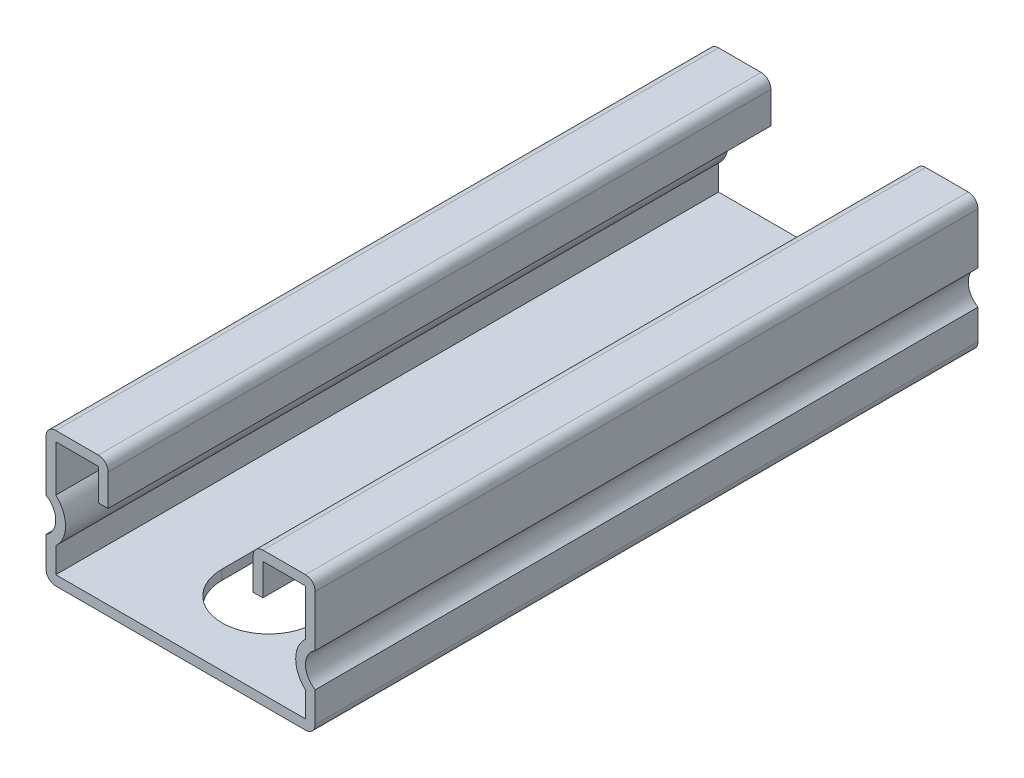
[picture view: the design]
ISO-10303-21;
HEADER;
FILE_DESCRIPTION(('STEP AP214'),'2;1');
FILE_NAME('part.step','',(''),(''),'','','');
FILE_SCHEMA(('AUTOMOTIVE_DESIGN { 1 0 10303 214 1 1 1 1 }'));
ENDSEC;
DATA;
#1=APPLICATION_CONTEXT('core data for automotive mechanical design processes');
#2=APPLICATION_PROTOCOL_DEFINITION('international standard','automotive_design',2000,#1);
#3=PRODUCT_CONTEXT('',#1,'mechanical');
#4=PRODUCT('Part','Part','',(#3));
#5=PRODUCT_RELATED_PRODUCT_CATEGORY('part','',(#4));
#6=PRODUCT_DEFINITION_FORMATION('','',#4);
#7=PRODUCT_DEFINITION_CONTEXT('part definition',#1,'design');
#8=PRODUCT_DEFINITION('design','',#6,#7);
#9=PRODUCT_DEFINITION_SHAPE('','',#8);
#10=(LENGTH_UNIT() NAMED_UNIT(*) SI_UNIT(.MILLI.,.METRE.));
#11=(NAMED_UNIT(*) PLANE_ANGLE_UNIT() SI_UNIT($,.RADIAN.));
#12=(NAMED_UNIT(*) SI_UNIT($,.STERADIAN.) SOLID_ANGLE_UNIT());
#13=UNCERTAINTY_MEASURE_WITH_UNIT(LENGTH_MEASURE(1.E-05),#10,'distance_accuracy_value','');
#14=(GEOMETRIC_REPRESENTATION_CONTEXT(3) GLOBAL_UNCERTAINTY_ASSIGNED_CONTEXT((#13)) GLOBAL_UNIT_ASSIGNED_CONTEXT((#10,
#11,#12)) REPRESENTATION_CONTEXT('',''));
#15=CARTESIAN_POINT('',(0.,0.,0.));
#16=DIRECTION('',(0.,0.,1.));
#17=DIRECTION('',(1.,0.,0.));
#18=AXIS2_PLACEMENT_3D('',#15,#16,#17);
#19=CARTESIAN_POINT('',(-19.1389,10.4394,101.6));
#20=DIRECTION('',(-1.,0.,0.));
#21=DIRECTION('',(0.,0.,1.));
#22=AXIS2_PLACEMENT_3D('',#19,#20,#21);
#23=PLANE('',#22);
#24=DIRECTION('',(0.,1.,0.));
#25=VECTOR('',#24,1.);
#26=CARTESIAN_POINT('',(-19.1389,10.4394,0.));
#27=LINE('',#26,#25);
#28=CARTESIAN_POINT('',(-19.1389,3.35097147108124,0.));
#29=VERTEX_POINT('',#28);
#30=CARTESIAN_POINT('',(-19.1389,10.4394,0.));
#31=VERTEX_POINT('',#30);
#32=EDGE_CURVE('E326',#29,#31,#27,.T.);
#33=ORIENTED_EDGE('',*,*,#32,.T.);
#34=DIRECTION('',(0.,0.,-1.));
#35=VECTOR('',#34,1.);
#36=CARTESIAN_POINT('',(-19.1389,10.4394,101.6));
#37=LINE('',#36,#35);
#38=CARTESIAN_POINT('',(-19.1389,10.4394,101.6));
#39=VERTEX_POINT('',#38);
#40=EDGE_CURVE('E541',#39,#31,#37,.T.);
#41=ORIENTED_EDGE('',*,*,#40,.F.);
#42=DIRECTION('',(0.,1.,0.));
#43=VECTOR('',#42,1.);
#44=CARTESIAN_POINT('',(-19.1389,10.4394,101.6));
#45=LINE('',#44,#43);
#46=CARTESIAN_POINT('',(-19.1389,3.35097147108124,101.6));
#47=VERTEX_POINT('',#46);
#48=EDGE_CURVE('E333',#47,#39,#45,.T.);
#49=ORIENTED_EDGE('',*,*,#48,.F.);
#50=DIRECTION('',(0.,0.,-1.));
#51=VECTOR('',#50,1.);
#52=CARTESIAN_POINT('',(-19.1389,3.35097147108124,101.6));
#53=LINE('',#52,#51);
#54=EDGE_CURVE('E395',#47,#29,#53,.T.);
#55=ORIENTED_EDGE('',*,*,#54,.T.);
#56=EDGE_LOOP('',(#33,#41,#49,#55));
#57=FACE_BOUND('',#56,.T.);
#58=ADVANCED_FACE('F33',(#57),#23,.F.);
#59=CARTESIAN_POINT('',(-19.1389,10.4394,101.6));
#60=DIRECTION('',(0.,1.,0.));
#61=DIRECTION('',(-1.,0.,0.));
#62=AXIS2_PLACEMENT_3D('',#59,#60,#61);
#63=PLANE('',#62);
#64=DIRECTION('',(1.,0.,0.));
#65=VECTOR('',#64,1.);
#66=CARTESIAN_POINT('',(-19.1389,10.4394,0.));
#67=LINE('',#66,#65);
#68=CARTESIAN_POINT('',(-12.6111,10.4394,0.));
#69=VERTEX_POINT('',#68);
#70=EDGE_CURVE('E398',#31,#69,#67,.T.);
#71=ORIENTED_EDGE('',*,*,#70,.T.);
#72=DIRECTION('',(0.,0.,-1.));
#73=VECTOR('',#72,1.);
#74=CARTESIAN_POINT('',(-12.6111,10.4394,101.6));
#75=LINE('',#74,#73);
#76=CARTESIAN_POINT('',(-12.6111,10.4394,101.6));
#77=VERTEX_POINT('',#76);
#78=EDGE_CURVE('E538',#77,#69,#75,.T.);
#79=ORIENTED_EDGE('',*,*,#78,.F.);
#80=DIRECTION('',(1.,0.,0.));
#81=VECTOR('',#80,1.);
#82=CARTESIAN_POINT('',(-19.1389,10.4394,101.6));
#83=LINE('',#82,#81);
#84=EDGE_CURVE('E336',#39,#77,#83,.T.);
#85=ORIENTED_EDGE('',*,*,#84,.F.);
#86=ORIENTED_EDGE('',*,*,#40,.T.);
#87=EDGE_LOOP('',(#71,#79,#85,#86));
#88=FACE_BOUND('',#87,.T.);
#89=ADVANCED_FACE('F582',(#88),#63,.F.);
#90=CARTESIAN_POINT('',(-12.6111,10.4394,101.6));
#91=DIRECTION('',(1.,0.,0.));
#92=DIRECTION('',(0.,0.,-1.));
#93=AXIS2_PLACEMENT_3D('',#90,#91,#92);
#94=PLANE('',#93);
#95=DIRECTION('',(0.,-1.,0.));
#96=VECTOR('',#95,1.);
#97=CARTESIAN_POINT('',(-12.6111,10.4394,0.));
#98=LINE('',#97,#96);
#99=CARTESIAN_POINT('',(-12.6111,5.588,0.));
#100=VERTEX_POINT('',#99);
#101=EDGE_CURVE('E400',#69,#100,#98,.T.);
#102=ORIENTED_EDGE('',*,*,#101,.T.);
#103=DIRECTION('',(0.,0.,-1.));
#104=VECTOR('',#103,1.);
#105=CARTESIAN_POINT('',(-12.6111,5.588,101.6));
#106=LINE('',#105,#104);
#107=CARTESIAN_POINT('',(-12.6111,5.588,101.6));
#108=VERTEX_POINT('',#107);
#109=EDGE_CURVE('E535',#108,#100,#106,.T.);
#110=ORIENTED_EDGE('',*,*,#109,.F.);
#111=DIRECTION('',(0.,-1.,0.));
#112=VECTOR('',#111,1.);
#113=CARTESIAN_POINT('',(-12.6111,10.4394,101.6));
#114=LINE('',#113,#112);
#115=EDGE_CURVE('E339',#77,#108,#114,.T.);
#116=ORIENTED_EDGE('',*,*,#115,.F.);
#117=ORIENTED_EDGE('',*,*,#78,.T.);
#118=EDGE_LOOP('',(#102,#110,#116,#117));
#119=FACE_BOUND('',#118,.T.);
#120=ADVANCED_FACE('F587',(#119),#94,.F.);
#121=CARTESIAN_POINT('',(-12.6111,5.588,101.6));
#122=DIRECTION('',(0.,1.,0.));
#123=DIRECTION('',(0.,0.,1.));
#124=AXIS2_PLACEMENT_3D('',#121,#122,#123);
#125=PLANE('',#124);
#126=DIRECTION('',(1.,0.,0.));
#127=VECTOR('',#126,1.);
#128=CARTESIAN_POINT('',(-12.6111,5.588,0.));
#129=LINE('',#128,#127);
#130=CARTESIAN_POINT('',(-11.1125,5.588,0.));
#131=VERTEX_POINT('',#130);
#132=EDGE_CURVE('E402',#100,#131,#129,.T.);
#133=ORIENTED_EDGE('',*,*,#132,.T.);
#134=DIRECTION('',(0.,0.,-1.));
#135=VECTOR('',#134,1.);
#136=CARTESIAN_POINT('',(-11.1125,5.588,101.6));
#137=LINE('',#136,#135);
#138=CARTESIAN_POINT('',(-11.1125,5.588,101.6));
#139=VERTEX_POINT('',#138);
#140=EDGE_CURVE('E532',#139,#131,#137,.T.);
#141=ORIENTED_EDGE('',*,*,#140,.F.);
#142=DIRECTION('',(1.,0.,0.));
#143=VECTOR('',#142,1.);
#144=CARTESIAN_POINT('',(-12.6111,5.588,101.6));
#145=LINE('',#144,#143);
#146=EDGE_CURVE('E341',#108,#139,#145,.T.);
#147=ORIENTED_EDGE('',*,*,#146,.F.);
#148=ORIENTED_EDGE('',*,*,#109,.T.);
#149=EDGE_LOOP('',(#133,#141,#147,#148));
#150=FACE_BOUND('',#149,.T.);
#151=ADVANCED_FACE('F728',(#150),#125,.F.);
#152=CARTESIAN_POINT('',(-11.1125,10.4394,101.6));
#153=DIRECTION('',(-1.,0.,0.));
#154=DIRECTION('',(0.,-1.,0.));
#155=AXIS2_PLACEMENT_3D('',#152,#153,#154);
#156=PLANE('',#155);
#157=DIRECTION('',(0.,1.,0.));
#158=VECTOR('',#157,1.);
#159=CARTESIAN_POINT('',(-11.1125,10.4394,0.));
#160=LINE('',#159,#158);
#161=CARTESIAN_POINT('',(-11.1125,10.4394,0.));
#162=VERTEX_POINT('',#161);
#163=EDGE_CURVE('E404',#131,#162,#160,.T.);
#164=ORIENTED_EDGE('',*,*,#163,.T.);
#165=DIRECTION('',(0.,0.,-1.));
#166=VECTOR('',#165,1.);
#167=CARTESIAN_POINT('',(-11.1125,10.4394,101.6));
#168=LINE('',#167,#166);
#169=CARTESIAN_POINT('',(-11.1125,10.4394,101.6));
#170=VERTEX_POINT('',#169);
#171=EDGE_CURVE('E529',#170,#162,#168,.T.);
#172=ORIENTED_EDGE('',*,*,#171,.F.);
#173=DIRECTION('',(0.,1.,0.));
#174=VECTOR('',#173,1.);
#175=CARTESIAN_POINT('',(-11.1125,10.4394,101.6));
#176=LINE('',#175,#174);
#177=EDGE_CURVE('E343',#139,#170,#176,.T.);
#178=ORIENTED_EDGE('',*,*,#177,.F.);
#179=ORIENTED_EDGE('',*,*,#140,.T.);
#180=EDGE_LOOP('',(#164,#172,#178,#179));
#181=FACE_BOUND('',#180,.T.);
#182=ADVANCED_FACE('F725',(#181),#156,.F.);
#183=CARTESIAN_POINT('',(-12.6111,10.4394,101.6));
#184=DIRECTION('',(0.,0.,-1.));
#185=DIRECTION('',(-1.,0.,0.));
#186=AXIS2_PLACEMENT_3D('',#183,#184,#185);
#187=CYLINDRICAL_SURFACE('',#186,1.4986);
#188=CARTESIAN_POINT('',(-12.6111,10.4394,0.));
#189=DIRECTION('',(0.,0.,1.));
#190=DIRECTION('',(-1.,0.,0.));
#191=AXIS2_PLACEMENT_3D('',#188,#189,#190);
#192=CIRCLE('',#191,1.4986);
#193=CARTESIAN_POINT('',(-12.6111,11.938,0.));
#194=VERTEX_POINT('',#193);
#195=EDGE_CURVE('E406',#162,#194,#192,.T.);
#196=ORIENTED_EDGE('',*,*,#195,.T.);
#197=DIRECTION('',(0.,0.,-1.));
#198=VECTOR('',#197,1.);
#199=CARTESIAN_POINT('',(-12.6111,11.938,101.6));
#200=LINE('',#199,#198);
#201=CARTESIAN_POINT('',(-12.6111,11.938,101.6));
#202=VERTEX_POINT('',#201);
#203=EDGE_CURVE('E526',#202,#194,#200,.T.);
#204=ORIENTED_EDGE('',*,*,#203,.F.);
#205=CARTESIAN_POINT('',(-12.6111,10.4394,101.6));
#206=DIRECTION('',(0.,0.,1.));
#207=DIRECTION('',(-1.,0.,0.));
#208=AXIS2_PLACEMENT_3D('',#205,#206,#207);
#209=CIRCLE('',#208,1.4986);
#210=EDGE_CURVE('E345',#170,#202,#209,.T.);
#211=ORIENTED_EDGE('',*,*,#210,.F.);
#212=ORIENTED_EDGE('',*,*,#171,.T.);
#213=EDGE_LOOP('',(#196,#204,#211,#212));
#214=FACE_BOUND('',#213,.T.);
#215=ADVANCED_FACE('F721',(#214),#187,.T.);
#216=CARTESIAN_POINT('',(-19.1389,11.938,101.6));
#217=DIRECTION('',(0.,-1.,0.));
#218=DIRECTION('',(0.,0.,-1.));
#219=AXIS2_PLACEMENT_3D('',#216,#217,#218);
#220=PLANE('',#219);
#221=DIRECTION('',(-1.,0.,0.));
#222=VECTOR('',#221,1.);
#223=CARTESIAN_POINT('',(-19.1389,11.938,0.));
#224=LINE('',#223,#222);
#225=CARTESIAN_POINT('',(-19.1389,11.938,0.));
#226=VERTEX_POINT('',#225);
#227=EDGE_CURVE('E408',#194,#226,#224,.T.);
#228=ORIENTED_EDGE('',*,*,#227,.T.);
#229=DIRECTION('',(0.,0.,-1.));
#230=VECTOR('',#229,1.);
#231=CARTESIAN_POINT('',(-19.1389,11.938,101.6));
#232=LINE('',#231,#230);
#233=CARTESIAN_POINT('',(-19.1389,11.938,101.6));
#234=VERTEX_POINT('',#233);
#235=EDGE_CURVE('E523',#234,#226,#232,.T.);
#236=ORIENTED_EDGE('',*,*,#235,.F.);
#237=DIRECTION('',(-1.,0.,0.));
#238=VECTOR('',#237,1.);
#239=CARTESIAN_POINT('',(-19.1389,11.938,101.6));
#240=LINE('',#239,#238);
#241=EDGE_CURVE('E347',#202,#234,#240,.T.);
#242=ORIENTED_EDGE('',*,*,#241,.F.);
#243=ORIENTED_EDGE('',*,*,#203,.T.);
#244=EDGE_LOOP('',(#228,#236,#242,#243));
#245=FACE_BOUND('',#244,.T.);
#246=ADVANCED_FACE('F716',(#245),#220,.F.);
#247=CARTESIAN_POINT('',(-19.1389,10.4394,101.6));
#248=DIRECTION('',(0.,0.,-1.));
#249=DIRECTION('',(-1.,0.,0.));
#250=AXIS2_PLACEMENT_3D('',#247,#248,#249);
#251=CYLINDRICAL_SURFACE('',#250,1.49860000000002);
#252=CARTESIAN_POINT('',(-19.1389,10.4394,0.));
#253=DIRECTION('',(0.,0.,1.));
#254=DIRECTION('',(-1.,0.,0.));
#255=AXIS2_PLACEMENT_3D('',#252,#253,#254);
#256=CIRCLE('',#255,1.49860000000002);
#257=CARTESIAN_POINT('',(-20.6375,10.4394,0.));
#258=VERTEX_POINT('',#257);
#259=EDGE_CURVE('E410',#226,#258,#256,.T.);
#260=ORIENTED_EDGE('',*,*,#259,.T.);
#261=DIRECTION('',(0.,0.,-1.));
#262=VECTOR('',#261,1.);
#263=CARTESIAN_POINT('',(-20.6375,10.4394,101.6));
#264=LINE('',#263,#262);
#265=CARTESIAN_POINT('',(-20.6375,10.4394,101.6));
#266=VERTEX_POINT('',#265);
#267=EDGE_CURVE('E520',#266,#258,#264,.T.);
#268=ORIENTED_EDGE('',*,*,#267,.F.);
#269=CARTESIAN_POINT('',(-19.1389,10.4394,101.6));
#270=DIRECTION('',(0.,0.,1.));
#271=DIRECTION('',(-1.,0.,0.));
#272=AXIS2_PLACEMENT_3D('',#269,#270,#271);
#273=CIRCLE('',#272,1.49860000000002);
#274=EDGE_CURVE('E349',#234,#266,#273,.T.);
#275=ORIENTED_EDGE('',*,*,#274,.F.);
#276=ORIENTED_EDGE('',*,*,#235,.T.);
#277=EDGE_LOOP('',(#260,#268,#275,#276));
#278=FACE_BOUND('',#277,.T.);
#279=ADVANCED_FACE('F710',(#278),#251,.T.);
#280=CARTESIAN_POINT('',(-20.6375,10.4394,101.6));
#281=DIRECTION('',(1.,0.,0.));
#282=DIRECTION('',(0.,1.,0.));
#283=AXIS2_PLACEMENT_3D('',#280,#281,#282);
#284=PLANE('',#283);
#285=DIRECTION('',(0.,-1.,0.));
#286=VECTOR('',#285,1.);
#287=CARTESIAN_POINT('',(-20.6375,10.4394,0.));
#288=LINE('',#287,#286);
#289=CARTESIAN_POINT('',(-20.6375,2.59565134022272,0.));
#290=VERTEX_POINT('',#289);
#291=EDGE_CURVE('E412',#258,#290,#288,.T.);
#292=ORIENTED_EDGE('',*,*,#291,.T.);
#293=DIRECTION('',(0.,0.,-1.));
#294=VECTOR('',#293,1.);
#295=CARTESIAN_POINT('',(-20.6375,2.59565134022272,101.6));
#296=LINE('',#295,#294);
#297=CARTESIAN_POINT('',(-20.6375,2.59565134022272,101.6));
#298=VERTEX_POINT('',#297);
#299=EDGE_CURVE('E517',#298,#290,#296,.T.);
#300=ORIENTED_EDGE('',*,*,#299,.F.);
#301=DIRECTION('',(0.,-1.,0.));
#302=VECTOR('',#301,1.);
#303=CARTESIAN_POINT('',(-20.6375,10.4394,101.6));
#304=LINE('',#303,#302);
#305=EDGE_CURVE('E351',#266,#298,#304,.T.);
#306=ORIENTED_EDGE('',*,*,#305,.F.);
#307=ORIENTED_EDGE('',*,*,#267,.T.);
#308=EDGE_LOOP('',(#292,#300,#306,#307));
#309=FACE_BOUND('',#308,.T.);
#310=ADVANCED_FACE('F706',(#309),#284,.F.);
#311=CARTESIAN_POINT('',(-22.1361,0.,101.6));
#312=DIRECTION('',(0.,0.,-1.));
#313=DIRECTION('',(-1.,0.,0.));
#314=AXIS2_PLACEMENT_3D('',#311,#312,#313);
#315=CYLINDRICAL_SURFACE('',#314,2.9972);
#316=CARTESIAN_POINT('',(-22.1361,0.,0.));
#317=DIRECTION('',(0.,0.,-1.));
#318=DIRECTION('',(1.,0.,0.));
#319=AXIS2_PLACEMENT_3D('',#316,#317,#318);
#320=CIRCLE('',#319,2.9972);
#321=CARTESIAN_POINT('',(-20.6375,-2.59565134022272,0.));
#322=VERTEX_POINT('',#321);
#323=EDGE_CURVE('E414',#290,#322,#320,.T.);
#324=ORIENTED_EDGE('',*,*,#323,.T.);
#325=DIRECTION('',(0.,0.,-1.));
#326=VECTOR('',#325,1.);
#327=CARTESIAN_POINT('',(-20.6375,-2.59565134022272,101.6));
#328=LINE('',#327,#326);
#329=CARTESIAN_POINT('',(-20.6375,-2.59565134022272,101.6));
#330=VERTEX_POINT('',#329);
#331=EDGE_CURVE('E514',#330,#322,#328,.T.);
#332=ORIENTED_EDGE('',*,*,#331,.F.);
#333=CARTESIAN_POINT('',(-22.1361,0.,101.6));
#334=DIRECTION('',(0.,0.,-1.));
#335=DIRECTION('',(1.,0.,0.));
#336=AXIS2_PLACEMENT_3D('',#333,#334,#335);
#337=CIRCLE('',#336,2.9972);
#338=EDGE_CURVE('E353',#298,#330,#337,.T.);
#339=ORIENTED_EDGE('',*,*,#338,.F.);
#340=ORIENTED_EDGE('',*,*,#299,.T.);
#341=EDGE_LOOP('',(#324,#332,#339,#340));
#342=FACE_BOUND('',#341,.T.);
#343=ADVANCED_FACE('F701',(#342),#315,.F.);
#344=CARTESIAN_POINT('',(-20.6375,-2.59565134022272,101.6));
#345=DIRECTION('',(1.,0.,0.));
#346=DIRECTION('',(0.,1.,0.));
#347=AXIS2_PLACEMENT_3D('',#344,#345,#346);
#348=PLANE('',#347);
#349=DIRECTION('',(0.,-1.,0.));
#350=VECTOR('',#349,1.);
#351=CARTESIAN_POINT('',(-20.6375,-2.59565134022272,0.));
#352=LINE('',#351,#350);
#353=CARTESIAN_POINT('',(-20.6375,-7.2136,0.));
#354=VERTEX_POINT('',#353);
#355=EDGE_CURVE('E416',#322,#354,#352,.T.);
#356=ORIENTED_EDGE('',*,*,#355,.T.);
#357=DIRECTION('',(0.,0.,-1.));
#358=VECTOR('',#357,1.);
#359=CARTESIAN_POINT('',(-20.6375,-7.2136,101.6));
#360=LINE('',#359,#358);
#361=CARTESIAN_POINT('',(-20.6375,-7.2136,101.6));
#362=VERTEX_POINT('',#361);
#363=EDGE_CURVE('E511',#362,#354,#360,.T.);
#364=ORIENTED_EDGE('',*,*,#363,.F.);
#365=DIRECTION('',(0.,-1.,0.));
#366=VECTOR('',#365,1.);
#367=CARTESIAN_POINT('',(-20.6375,-2.59565134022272,101.6));
#368=LINE('',#367,#366);
#369=EDGE_CURVE('E355',#330,#362,#368,.T.);
#370=ORIENTED_EDGE('',*,*,#369,.F.);
#371=ORIENTED_EDGE('',*,*,#331,.T.);
#372=EDGE_LOOP('',(#356,#364,#370,#371));
#373=FACE_BOUND('',#372,.T.);
#374=ADVANCED_FACE('F695',(#373),#348,.F.);
#375=CARTESIAN_POINT('',(-19.1389,-7.2136,101.6));
#376=DIRECTION('',(0.,0.,-1.));
#377=DIRECTION('',(-1.,0.,0.));
#378=AXIS2_PLACEMENT_3D('',#375,#376,#377);
#379=CYLINDRICAL_SURFACE('',#378,1.4986);
#380=CARTESIAN_POINT('',(-19.1389,-7.2136,0.));
#381=DIRECTION('',(0.,0.,1.));
#382=DIRECTION('',(-1.,0.,0.));
#383=AXIS2_PLACEMENT_3D('',#380,#381,#382);
#384=CIRCLE('',#383,1.4986);
#385=CARTESIAN_POINT('',(-19.1389,-8.7122,0.));
#386=VERTEX_POINT('',#385);
#387=EDGE_CURVE('E418',#354,#386,#384,.T.);
#388=ORIENTED_EDGE('',*,*,#387,.T.);
#389=DIRECTION('',(0.,0.,-1.));
#390=VECTOR('',#389,1.);
#391=CARTESIAN_POINT('',(-19.1389,-8.7122,101.6));
#392=LINE('',#391,#390);
#393=CARTESIAN_POINT('',(-19.1389,-8.7122,101.6));
#394=VERTEX_POINT('',#393);
#395=EDGE_CURVE('E508',#394,#386,#392,.T.);
#396=ORIENTED_EDGE('',*,*,#395,.F.);
#397=CARTESIAN_POINT('',(-19.1389,-7.2136,101.6));
#398=DIRECTION('',(0.,0.,1.));
#399=DIRECTION('',(-1.,0.,0.));
#400=AXIS2_PLACEMENT_3D('',#397,#398,#399);
#401=CIRCLE('',#400,1.4986);
#402=EDGE_CURVE('E357',#362,#394,#401,.T.);
#403=ORIENTED_EDGE('',*,*,#402,.F.);
#404=ORIENTED_EDGE('',*,*,#363,.T.);
#405=EDGE_LOOP('',(#388,#396,#403,#404));
#406=FACE_BOUND('',#405,.T.);
#407=ADVANCED_FACE('F691',(#406),#379,.T.);
#408=CARTESIAN_POINT('',(-19.1389,-8.7122,101.6));
#409=DIRECTION('',(0.,1.,0.));
#410=DIRECTION('',(0.,0.,1.));
#411=AXIS2_PLACEMENT_3D('',#408,#409,#410);
#412=PLANE('',#411);
#413=DIRECTION('',(0.,0.,-1.));
#414=VECTOR('',#413,1.);
#415=CARTESIAN_POINT('',(-7.14375,-8.71219999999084,73.81875));
#416=LINE('',#415,#414);
#417=CARTESIAN_POINT('',(-7.14375,-8.7122,88.10625));
#418=VERTEX_POINT('',#417);
#419=CARTESIAN_POINT('',(-7.14375,-8.71219999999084,73.81875));
#420=VERTEX_POINT('',#419);
#421=EDGE_CURVE('E279',#418,#420,#416,.T.);
#422=ORIENTED_EDGE('',*,*,#421,.F.);
#423=CARTESIAN_POINT('',(0.,-8.71219999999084,88.10625));
#424=DIRECTION('',(0.,-1.,0.));
#425=DIRECTION('',(0.,0.,-1.));
#426=AXIS2_PLACEMENT_3D('',#423,#424,#425);
#427=CIRCLE('',#426,7.14375);
#428=CARTESIAN_POINT('',(7.14375,-8.71219999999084,88.10625));
#429=VERTEX_POINT('',#428);
#430=EDGE_CURVE('E47',#429,#418,#427,.T.);
#431=ORIENTED_EDGE('',*,*,#430,.F.);
#432=DIRECTION('',(0.,0.,1.));
#433=VECTOR('',#432,1.);
#434=CARTESIAN_POINT('',(7.14375,-8.71219999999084,88.10625));
#435=LINE('',#434,#433);
#436=CARTESIAN_POINT('',(7.14375,-8.71219999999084,73.81875));
#437=VERTEX_POINT('',#436);
#438=EDGE_CURVE('E295',#437,#429,#435,.T.);
#439=ORIENTED_EDGE('',*,*,#438,.F.);
#440=CARTESIAN_POINT('',(0.,-8.71219999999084,73.81875));
#441=DIRECTION('',(0.,-1.,0.));
#442=DIRECTION('',(0.,0.,-1.));
#443=AXIS2_PLACEMENT_3D('',#440,#441,#442);
#444=CIRCLE('',#443,7.14375);
#445=EDGE_CURVE('E289',#420,#437,#444,.T.);
#446=ORIENTED_EDGE('',*,*,#445,.F.);
#447=EDGE_LOOP('',(#422,#431,#439,#446));
#448=FACE_BOUND('',#447,.T.);
#449=DIRECTION('',(0.,0.,-1.));
#450=VECTOR('',#449,1.);
#451=CARTESIAN_POINT('',(-7.14375,-8.71219999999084,23.01875));
#452=LINE('',#451,#450);
#453=CARTESIAN_POINT('',(-7.14375,-8.7122,37.30625));
#454=VERTEX_POINT('',#453);
#455=CARTESIAN_POINT('',(-7.14375,-8.71219999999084,23.01875));
#456=VERTEX_POINT('',#455);
#457=EDGE_CURVE('E314',#454,#456,#452,.T.);
#458=ORIENTED_EDGE('',*,*,#457,.F.);
#459=CARTESIAN_POINT('',(0.,-8.71219999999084,37.30625));
#460=DIRECTION('',(0.,-1.,0.));
#461=DIRECTION('',(0.,0.,-1.));
#462=AXIS2_PLACEMENT_3D('',#459,#460,#461);
#463=CIRCLE('',#462,7.14375);
#464=CARTESIAN_POINT('',(7.14375,-8.71219999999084,37.30625));
#465=VERTEX_POINT('',#464);
#466=EDGE_CURVE('E312',#465,#454,#463,.T.);
#467=ORIENTED_EDGE('',*,*,#466,.F.);
#468=DIRECTION('',(0.,0.,1.));
#469=VECTOR('',#468,1.);
#470=CARTESIAN_POINT('',(7.14375,-8.71219999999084,37.30625));
#471=LINE('',#470,#469);
#472=CARTESIAN_POINT('',(7.14375,-8.71219999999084,23.01875));
#473=VERTEX_POINT('',#472);
#474=EDGE_CURVE('E320',#473,#465,#471,.T.);
#475=ORIENTED_EDGE('',*,*,#474,.F.);
#476=CARTESIAN_POINT('',(0.,-8.71219999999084,23.01875));
#477=DIRECTION('',(0.,-1.,0.));
#478=DIRECTION('',(0.,0.,-1.));
#479=AXIS2_PLACEMENT_3D('',#476,#477,#478);
#480=CIRCLE('',#479,7.14375);
#481=EDGE_CURVE('E317',#456,#473,#480,.T.);
#482=ORIENTED_EDGE('',*,*,#481,.F.);
#483=EDGE_LOOP('',(#458,#467,#475,#482));
#484=FACE_BOUND('',#483,.T.);
#485=DIRECTION('',(1.,0.,0.));
#486=VECTOR('',#485,1.);
#487=CARTESIAN_POINT('',(-19.1389,-8.7122,0.));
#488=LINE('',#487,#486);
#489=CARTESIAN_POINT('',(19.1389,-8.7122,0.));
#490=VERTEX_POINT('',#489);
#491=EDGE_CURVE('E420',#386,#490,#488,.T.);
#492=ORIENTED_EDGE('',*,*,#491,.T.);
#493=DIRECTION('',(0.,0.,-1.));
#494=VECTOR('',#493,1.);
#495=CARTESIAN_POINT('',(19.1389,-8.7122,101.6));
#496=LINE('',#495,#494);
#497=CARTESIAN_POINT('',(19.1389,-8.7122,101.6));
#498=VERTEX_POINT('',#497);
#499=EDGE_CURVE('E505',#498,#490,#496,.T.);
#500=ORIENTED_EDGE('',*,*,#499,.F.);
#501=DIRECTION('',(1.,0.,0.));
#502=VECTOR('',#501,1.);
#503=CARTESIAN_POINT('',(-19.1389,-8.7122,101.6));
#504=LINE('',#503,#502);
#505=EDGE_CURVE('E359',#394,#498,#504,.T.);
#506=ORIENTED_EDGE('',*,*,#505,.F.);
#507=ORIENTED_EDGE('',*,*,#395,.T.);
#508=EDGE_LOOP('',(#492,#500,#506,#507));
#509=FACE_BOUND('',#508,.T.);
#510=ADVANCED_FACE('F293',(#448,#484,#509),#412,.F.);
#511=CARTESIAN_POINT('',(19.1389,-7.2136,101.6));
#512=DIRECTION('',(0.,0.,-1.));
#513=DIRECTION('',(-1.,0.,0.));
#514=AXIS2_PLACEMENT_3D('',#511,#512,#513);
#515=CYLINDRICAL_SURFACE('',#514,1.4986);
#516=CARTESIAN_POINT('',(19.1389,-7.2136,0.));
#517=DIRECTION('',(0.,0.,1.));
#518=DIRECTION('',(-1.,0.,0.));
#519=AXIS2_PLACEMENT_3D('',#516,#517,#518);
#520=CIRCLE('',#519,1.4986);
#521=CARTESIAN_POINT('',(20.6375,-7.2136,0.));
#522=VERTEX_POINT('',#521);
#523=EDGE_CURVE('E422',#490,#522,#520,.T.);
#524=ORIENTED_EDGE('',*,*,#523,.T.);
#525=DIRECTION('',(0.,0.,-1.));
#526=VECTOR('',#525,1.);
#527=CARTESIAN_POINT('',(20.6375,-7.2136,101.6));
#528=LINE('',#527,#526);
#529=CARTESIAN_POINT('',(20.6375,-7.2136,101.6));
#530=VERTEX_POINT('',#529);
#531=EDGE_CURVE('E502',#530,#522,#528,.T.);
#532=ORIENTED_EDGE('',*,*,#531,.F.);
#533=CARTESIAN_POINT('',(19.1389,-7.2136,101.6));
#534=DIRECTION('',(0.,0.,1.));
#535=DIRECTION('',(-1.,0.,0.));
#536=AXIS2_PLACEMENT_3D('',#533,#534,#535);
#537=CIRCLE('',#536,1.4986);
#538=EDGE_CURVE('E361',#498,#530,#537,.T.);
#539=ORIENTED_EDGE('',*,*,#538,.F.);
#540=ORIENTED_EDGE('',*,*,#499,.T.);
#541=EDGE_LOOP('',(#524,#532,#539,#540));
#542=FACE_BOUND('',#541,.T.);
#543=ADVANCED_FACE('F682',(#542),#515,.T.);
#544=CARTESIAN_POINT('',(20.6375,-7.2136,101.6));
#545=DIRECTION('',(-1.,0.,0.));
#546=DIRECTION('',(0.,0.,1.));
#547=AXIS2_PLACEMENT_3D('',#544,#545,#546);
#548=PLANE('',#547);
#549=DIRECTION('',(0.,1.,0.));
#550=VECTOR('',#549,1.);
#551=CARTESIAN_POINT('',(20.6375,-7.2136,0.));
#552=LINE('',#551,#550);
#553=CARTESIAN_POINT('',(20.6375,-2.59565134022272,0.));
#554=VERTEX_POINT('',#553);
#555=EDGE_CURVE('E424',#522,#554,#552,.T.);
#556=ORIENTED_EDGE('',*,*,#555,.T.);
#557=DIRECTION('',(0.,0.,-1.));
#558=VECTOR('',#557,1.);
#559=CARTESIAN_POINT('',(20.6375,-2.59565134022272,101.6));
#560=LINE('',#559,#558);
#561=CARTESIAN_POINT('',(20.6375,-2.59565134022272,101.6));
#562=VERTEX_POINT('',#561);
#563=EDGE_CURVE('E499',#562,#554,#560,.T.);
#564=ORIENTED_EDGE('',*,*,#563,.F.);
#565=DIRECTION('',(0.,1.,0.));
#566=VECTOR('',#565,1.);
#567=CARTESIAN_POINT('',(20.6375,-7.2136,101.6));
#568=LINE('',#567,#566);
#569=EDGE_CURVE('E363',#530,#562,#568,.T.);
#570=ORIENTED_EDGE('',*,*,#569,.F.);
#571=ORIENTED_EDGE('',*,*,#531,.T.);
#572=EDGE_LOOP('',(#556,#564,#570,#571));
#573=FACE_BOUND('',#572,.T.);
#574=ADVANCED_FACE('F678',(#573),#548,.F.);
#575=CARTESIAN_POINT('',(22.1361,0.,101.6));
#576=DIRECTION('',(0.,0.,-1.));
#577=DIRECTION('',(-1.,0.,0.));
#578=AXIS2_PLACEMENT_3D('',#575,#576,#577);
#579=CYLINDRICAL_SURFACE('',#578,2.9972);
#580=CARTESIAN_POINT('',(22.1361,0.,0.));
#581=DIRECTION('',(0.,0.,-1.));
#582=DIRECTION('',(1.,0.,0.));
#583=AXIS2_PLACEMENT_3D('',#580,#581,#582);
#584=CIRCLE('',#583,2.9972);
#585=CARTESIAN_POINT('',(20.6375,2.59565134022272,0.));
#586=VERTEX_POINT('',#585);
#587=EDGE_CURVE('E426',#554,#586,#584,.T.);
#588=ORIENTED_EDGE('',*,*,#587,.T.);
#589=DIRECTION('',(0.,0.,-1.));
#590=VECTOR('',#589,1.);
#591=CARTESIAN_POINT('',(20.6375,2.59565134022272,101.6));
#592=LINE('',#591,#590);
#593=CARTESIAN_POINT('',(20.6375,2.59565134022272,101.6));
#594=VERTEX_POINT('',#593);
#595=EDGE_CURVE('E496',#594,#586,#592,.T.);
#596=ORIENTED_EDGE('',*,*,#595,.F.);
#597=CARTESIAN_POINT('',(22.1361,0.,101.6));
#598=DIRECTION('',(0.,0.,-1.));
#599=DIRECTION('',(1.,0.,0.));
#600=AXIS2_PLACEMENT_3D('',#597,#598,#599);
#601=CIRCLE('',#600,2.9972);
#602=EDGE_CURVE('E365',#562,#594,#601,.T.);
#603=ORIENTED_EDGE('',*,*,#602,.F.);
#604=ORIENTED_EDGE('',*,*,#563,.T.);
#605=EDGE_LOOP('',(#588,#596,#603,#604));
#606=FACE_BOUND('',#605,.T.);
#607=ADVANCED_FACE('F673',(#606),#579,.F.);
#608=CARTESIAN_POINT('',(20.6375,2.59565134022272,101.6));
#609=DIRECTION('',(-1.,0.,0.));
#610=DIRECTION('',(0.,-1.,0.));
#611=AXIS2_PLACEMENT_3D('',#608,#609,#610);
#612=PLANE('',#611);
#613=DIRECTION('',(0.,1.,0.));
#614=VECTOR('',#613,1.);
#615=CARTESIAN_POINT('',(20.6375,2.59565134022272,0.));
#616=LINE('',#615,#614);
#617=CARTESIAN_POINT('',(20.6375,10.4394,0.));
#618=VERTEX_POINT('',#617);
#619=EDGE_CURVE('E428',#586,#618,#616,.T.);
#620=ORIENTED_EDGE('',*,*,#619,.T.);
#621=DIRECTION('',(0.,0.,-1.));
#622=VECTOR('',#621,1.);
#623=CARTESIAN_POINT('',(20.6375,10.4394,101.6));
#624=LINE('',#623,#622);
#625=CARTESIAN_POINT('',(20.6375,10.4394,101.6));
#626=VERTEX_POINT('',#625);
#627=EDGE_CURVE('E493',#626,#618,#624,.T.);
#628=ORIENTED_EDGE('',*,*,#627,.F.);
#629=DIRECTION('',(0.,1.,0.));
#630=VECTOR('',#629,1.);
#631=CARTESIAN_POINT('',(20.6375,2.59565134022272,101.6));
#632=LINE('',#631,#630);
#633=EDGE_CURVE('E367',#594,#626,#632,.T.);
#634=ORIENTED_EDGE('',*,*,#633,.F.);
#635=ORIENTED_EDGE('',*,*,#595,.T.);
#636=EDGE_LOOP('',(#620,#628,#634,#635));
#637=FACE_BOUND('',#636,.T.);
#638=ADVANCED_FACE('F667',(#637),#612,.F.);
#639=CARTESIAN_POINT('',(19.1389,10.4394,101.6));
#640=DIRECTION('',(0.,0.,-1.));
#641=DIRECTION('',(-1.,0.,0.));
#642=AXIS2_PLACEMENT_3D('',#639,#640,#641);
#643=CYLINDRICAL_SURFACE('',#642,1.4986);
#644=CARTESIAN_POINT('',(19.1389,10.4394,0.));
#645=DIRECTION('',(0.,0.,1.));
#646=DIRECTION('',(-1.,0.,0.));
#647=AXIS2_PLACEMENT_3D('',#644,#645,#646);
#648=CIRCLE('',#647,1.4986);
#649=CARTESIAN_POINT('',(19.1389,11.938,0.));
#650=VERTEX_POINT('',#649);
#651=EDGE_CURVE('E430',#618,#650,#648,.T.);
#652=ORIENTED_EDGE('',*,*,#651,.T.);
#653=DIRECTION('',(0.,0.,-1.));
#654=VECTOR('',#653,1.);
#655=CARTESIAN_POINT('',(19.1389,11.938,101.6));
#656=LINE('',#655,#654);
#657=CARTESIAN_POINT('',(19.1389,11.938,101.6));
#658=VERTEX_POINT('',#657);
#659=EDGE_CURVE('E490',#658,#650,#656,.T.);
#660=ORIENTED_EDGE('',*,*,#659,.F.);
#661=CARTESIAN_POINT('',(19.1389,10.4394,101.6));
#662=DIRECTION('',(0.,0.,1.));
#663=DIRECTION('',(-1.,0.,0.));
#664=AXIS2_PLACEMENT_3D('',#661,#662,#663);
#665=CIRCLE('',#664,1.4986);
#666=EDGE_CURVE('E369',#626,#658,#665,.T.);
#667=ORIENTED_EDGE('',*,*,#666,.F.);
#668=ORIENTED_EDGE('',*,*,#627,.T.);
#669=EDGE_LOOP('',(#652,#660,#667,#668));
#670=FACE_BOUND('',#669,.T.);
#671=ADVANCED_FACE('F663',(#670),#643,.T.);
#672=CARTESIAN_POINT('',(19.1389,11.938,101.6));
#673=DIRECTION('',(0.,-1.,0.));
#674=DIRECTION('',(1.,0.,0.));
#675=AXIS2_PLACEMENT_3D('',#672,#673,#674);
#676=PLANE('',#675);
#677=DIRECTION('',(-1.,0.,0.));
#678=VECTOR('',#677,1.);
#679=CARTESIAN_POINT('',(19.1389,11.938,0.));
#680=LINE('',#679,#678);
#681=CARTESIAN_POINT('',(12.6111,11.938,0.));
#682=VERTEX_POINT('',#681);
#683=EDGE_CURVE('E432',#650,#682,#680,.T.);
#684=ORIENTED_EDGE('',*,*,#683,.T.);
#685=DIRECTION('',(0.,0.,-1.));
#686=VECTOR('',#685,1.);
#687=CARTESIAN_POINT('',(12.6111,11.938,101.6));
#688=LINE('',#687,#686);
#689=CARTESIAN_POINT('',(12.6111,11.938,101.6));
#690=VERTEX_POINT('',#689);
#691=EDGE_CURVE('E487',#690,#682,#688,.T.);
#692=ORIENTED_EDGE('',*,*,#691,.F.);
#693=DIRECTION('',(-1.,0.,0.));
#694=VECTOR('',#693,1.);
#695=CARTESIAN_POINT('',(19.1389,11.938,101.6));
#696=LINE('',#695,#694);
#697=EDGE_CURVE('E371',#658,#690,#696,.T.);
#698=ORIENTED_EDGE('',*,*,#697,.F.);
#699=ORIENTED_EDGE('',*,*,#659,.T.);
#700=EDGE_LOOP('',(#684,#692,#698,#699));
#701=FACE_BOUND('',#700,.T.);
#702=ADVANCED_FACE('F658',(#701),#676,.F.);
#703=CARTESIAN_POINT('',(12.6111,10.4394,101.6));
#704=DIRECTION('',(0.,0.,-1.));
#705=DIRECTION('',(-1.,0.,0.));
#706=AXIS2_PLACEMENT_3D('',#703,#704,#705);
#707=CYLINDRICAL_SURFACE('',#706,1.4986);
#708=CARTESIAN_POINT('',(12.6111,10.4394,0.));
#709=DIRECTION('',(0.,0.,1.));
#710=DIRECTION('',(-1.,0.,0.));
#711=AXIS2_PLACEMENT_3D('',#708,#709,#710);
#712=CIRCLE('',#711,1.4986);
#713=CARTESIAN_POINT('',(11.1125,10.4394,0.));
#714=VERTEX_POINT('',#713);
#715=EDGE_CURVE('E434',#682,#714,#712,.T.);
#716=ORIENTED_EDGE('',*,*,#715,.T.);
#717=DIRECTION('',(0.,0.,-1.));
#718=VECTOR('',#717,1.);
#719=CARTESIAN_POINT('',(11.1125,10.4394,101.6));
#720=LINE('',#719,#718);
#721=CARTESIAN_POINT('',(11.1125,10.4394,101.6));
#722=VERTEX_POINT('',#721);
#723=EDGE_CURVE('E484',#722,#714,#720,.T.);
#724=ORIENTED_EDGE('',*,*,#723,.F.);
#725=CARTESIAN_POINT('',(12.6111,10.4394,101.6));
#726=DIRECTION('',(0.,0.,1.));
#727=DIRECTION('',(-1.,0.,0.));
#728=AXIS2_PLACEMENT_3D('',#725,#726,#727);
#729=CIRCLE('',#728,1.4986);
#730=EDGE_CURVE('E373',#690,#722,#729,.T.);
#731=ORIENTED_EDGE('',*,*,#730,.F.);
#732=ORIENTED_EDGE('',*,*,#691,.T.);
#733=EDGE_LOOP('',(#716,#724,#731,#732));
#734=FACE_BOUND('',#733,.T.);
#735=ADVANCED_FACE('F652',(#734),#707,.T.);
#736=CARTESIAN_POINT('',(11.1125,10.4394,101.6));
#737=DIRECTION('',(1.,0.,0.));
#738=DIRECTION('',(0.,0.,-1.));
#739=AXIS2_PLACEMENT_3D('',#736,#737,#738);
#740=PLANE('',#739);
#741=DIRECTION('',(0.,-1.,0.));
#742=VECTOR('',#741,1.);
#743=CARTESIAN_POINT('',(11.1125,10.4394,0.));
#744=LINE('',#743,#742);
#745=CARTESIAN_POINT('',(11.1125,5.588,0.));
#746=VERTEX_POINT('',#745);
#747=EDGE_CURVE('E436',#714,#746,#744,.T.);
#748=ORIENTED_EDGE('',*,*,#747,.T.);
#749=DIRECTION('',(0.,0.,-1.));
#750=VECTOR('',#749,1.);
#751=CARTESIAN_POINT('',(11.1125,5.588,101.6));
#752=LINE('',#751,#750);
#753=CARTESIAN_POINT('',(11.1125,5.588,101.6));
#754=VERTEX_POINT('',#753);
#755=EDGE_CURVE('E481',#754,#746,#752,.T.);
#756=ORIENTED_EDGE('',*,*,#755,.F.);
#757=DIRECTION('',(0.,-1.,0.));
#758=VECTOR('',#757,1.);
#759=CARTESIAN_POINT('',(11.1125,10.4394,101.6));
#760=LINE('',#759,#758);
#761=EDGE_CURVE('E375',#722,#754,#760,.T.);
#762=ORIENTED_EDGE('',*,*,#761,.F.);
#763=ORIENTED_EDGE('',*,*,#723,.T.);
#764=EDGE_LOOP('',(#748,#756,#762,#763));
#765=FACE_BOUND('',#764,.T.);
#766=ADVANCED_FACE('F648',(#765),#740,.F.);
#767=CARTESIAN_POINT('',(11.1125,5.588,101.6));
#768=DIRECTION('',(0.,1.,0.));
#769=DIRECTION('',(-1.,0.,0.));
#770=AXIS2_PLACEMENT_3D('',#767,#768,#769);
#771=PLANE('',#770);
#772=DIRECTION('',(1.,0.,0.));
#773=VECTOR('',#772,1.);
#774=CARTESIAN_POINT('',(11.1125,5.588,0.));
#775=LINE('',#774,#773);
#776=CARTESIAN_POINT('',(12.6111,5.588,0.));
#777=VERTEX_POINT('',#776);
#778=EDGE_CURVE('E438',#746,#777,#775,.T.);
#779=ORIENTED_EDGE('',*,*,#778,.T.);
#780=DIRECTION('',(0.,0.,-1.));
#781=VECTOR('',#780,1.);
#782=CARTESIAN_POINT('',(12.6111,5.588,101.6));
#783=LINE('',#782,#781);
#784=CARTESIAN_POINT('',(12.6111,5.588,101.6));
#785=VERTEX_POINT('',#784);
#786=EDGE_CURVE('E478',#785,#777,#783,.T.);
#787=ORIENTED_EDGE('',*,*,#786,.F.);
#788=DIRECTION('',(1.,0.,0.));
#789=VECTOR('',#788,1.);
#790=CARTESIAN_POINT('',(11.1125,5.588,101.6));
#791=LINE('',#790,#789);
#792=EDGE_CURVE('E377',#754,#785,#791,.T.);
#793=ORIENTED_EDGE('',*,*,#792,.F.);
#794=ORIENTED_EDGE('',*,*,#755,.T.);
#795=EDGE_LOOP('',(#779,#787,#793,#794));
#796=FACE_BOUND('',#795,.T.);
#797=ADVANCED_FACE('F643',(#796),#771,.F.);
#798=CARTESIAN_POINT('',(12.6111,10.4394,101.6));
#799=DIRECTION('',(-1.,0.,0.));
#800=DIRECTION('',(0.,0.,1.));
#801=AXIS2_PLACEMENT_3D('',#798,#799,#800);
#802=PLANE('',#801);
#803=DIRECTION('',(0.,1.,0.));
#804=VECTOR('',#803,1.);
#805=CARTESIAN_POINT('',(12.6111,10.4394,0.));
#806=LINE('',#805,#804);
#807=CARTESIAN_POINT('',(12.6111,10.4394,0.));
#808=VERTEX_POINT('',#807);
#809=EDGE_CURVE('E440',#777,#808,#806,.T.);
#810=ORIENTED_EDGE('',*,*,#809,.T.);
#811=DIRECTION('',(0.,0.,-1.));
#812=VECTOR('',#811,1.);
#813=CARTESIAN_POINT('',(12.6111,10.4394,101.6));
#814=LINE('',#813,#812);
#815=CARTESIAN_POINT('',(12.6111,10.4394,101.6));
#816=VERTEX_POINT('',#815);
#817=EDGE_CURVE('E475',#816,#808,#814,.T.);
#818=ORIENTED_EDGE('',*,*,#817,.F.);
#819=DIRECTION('',(0.,1.,0.));
#820=VECTOR('',#819,1.);
#821=CARTESIAN_POINT('',(12.6111,10.4394,101.6));
#822=LINE('',#821,#820);
#823=EDGE_CURVE('E379',#785,#816,#822,.T.);
#824=ORIENTED_EDGE('',*,*,#823,.F.);
#825=ORIENTED_EDGE('',*,*,#786,.T.);
#826=EDGE_LOOP('',(#810,#818,#824,#825));
#827=FACE_BOUND('',#826,.T.);
#828=ADVANCED_FACE('F637',(#827),#802,.F.);
#829=CARTESIAN_POINT('',(19.1389,10.4394,101.6));
#830=DIRECTION('',(0.,1.,0.));
#831=DIRECTION('',(-1.,0.,0.));
#832=AXIS2_PLACEMENT_3D('',#829,#830,#831);
#833=PLANE('',#832);
#834=DIRECTION('',(1.,0.,0.));
#835=VECTOR('',#834,1.);
#836=CARTESIAN_POINT('',(19.1389,10.4394,0.));
#837=LINE('',#836,#835);
#838=CARTESIAN_POINT('',(19.1389,10.4394,0.));
#839=VERTEX_POINT('',#838);
#840=EDGE_CURVE('E442',#808,#839,#837,.T.);
#841=ORIENTED_EDGE('',*,*,#840,.T.);
#842=DIRECTION('',(0.,0.,-1.));
#843=VECTOR('',#842,1.);
#844=CARTESIAN_POINT('',(19.1389,10.4394,101.6));
#845=LINE('',#844,#843);
#846=CARTESIAN_POINT('',(19.1389,10.4394,101.6));
#847=VERTEX_POINT('',#846);
#848=EDGE_CURVE('E472',#847,#839,#845,.T.);
#849=ORIENTED_EDGE('',*,*,#848,.F.);
#850=DIRECTION('',(1.,0.,0.));
#851=VECTOR('',#850,1.);
#852=CARTESIAN_POINT('',(19.1389,10.4394,101.6));
#853=LINE('',#852,#851);
#854=EDGE_CURVE('E381',#816,#847,#853,.T.);
#855=ORIENTED_EDGE('',*,*,#854,.F.);
#856=ORIENTED_EDGE('',*,*,#817,.T.);
#857=EDGE_LOOP('',(#841,#849,#855,#856));
#858=FACE_BOUND('',#857,.T.);
#859=ADVANCED_FACE('F633',(#858),#833,.F.);
#860=CARTESIAN_POINT('',(19.1389,3.35097147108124,101.6));
#861=DIRECTION('',(1.,0.,0.));
#862=DIRECTION('',(0.,1.,0.));
#863=AXIS2_PLACEMENT_3D('',#860,#861,#862);
#864=PLANE('',#863);
#865=DIRECTION('',(0.,-1.,0.));
#866=VECTOR('',#865,1.);
#867=CARTESIAN_POINT('',(19.1389,3.35097147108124,0.));
#868=LINE('',#867,#866);
#869=CARTESIAN_POINT('',(19.1389,3.35097147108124,0.));
#870=VERTEX_POINT('',#869);
#871=EDGE_CURVE('E444',#839,#870,#868,.T.);
#872=ORIENTED_EDGE('',*,*,#871,.T.);
#873=DIRECTION('',(0.,0.,-1.));
#874=VECTOR('',#873,1.);
#875=CARTESIAN_POINT('',(19.1389,3.35097147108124,101.6));
#876=LINE('',#875,#874);
#877=CARTESIAN_POINT('',(19.1389,3.35097147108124,101.6));
#878=VERTEX_POINT('',#877);
#879=EDGE_CURVE('E469',#878,#870,#876,.T.);
#880=ORIENTED_EDGE('',*,*,#879,.F.);
#881=DIRECTION('',(0.,-1.,0.));
#882=VECTOR('',#881,1.);
#883=CARTESIAN_POINT('',(19.1389,3.35097147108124,101.6));
#884=LINE('',#883,#882);
#885=EDGE_CURVE('E383',#847,#878,#884,.T.);
#886=ORIENTED_EDGE('',*,*,#885,.F.);
#887=ORIENTED_EDGE('',*,*,#848,.T.);
#888=EDGE_LOOP('',(#872,#880,#886,#887));
#889=FACE_BOUND('',#888,.T.);
#890=ADVANCED_FACE('F628',(#889),#864,.F.);
#891=CARTESIAN_POINT('',(22.1361,0.,101.6));
#892=DIRECTION('',(0.,0.,-1.));
#893=DIRECTION('',(-1.,0.,0.));
#894=AXIS2_PLACEMENT_3D('',#891,#892,#893);
#895=CYLINDRICAL_SURFACE('',#894,4.49580000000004);
#896=CARTESIAN_POINT('',(22.1361,0.,0.));
#897=DIRECTION('',(0.,0.,1.));
#898=DIRECTION('',(1.,0.,0.));
#899=AXIS2_PLACEMENT_3D('',#896,#897,#898);
#900=CIRCLE('',#899,4.49580000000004);
#901=CARTESIAN_POINT('',(19.1389,-3.35097147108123,0.));
#902=VERTEX_POINT('',#901);
#903=EDGE_CURVE('E446',#870,#902,#900,.T.);
#904=ORIENTED_EDGE('',*,*,#903,.T.);
#905=DIRECTION('',(0.,0.,-1.));
#906=VECTOR('',#905,1.);
#907=CARTESIAN_POINT('',(19.1389,-3.35097147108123,101.6));
#908=LINE('',#907,#906);
#909=CARTESIAN_POINT('',(19.1389,-3.35097147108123,101.6));
#910=VERTEX_POINT('',#909);
#911=EDGE_CURVE('E466',#910,#902,#908,.T.);
#912=ORIENTED_EDGE('',*,*,#911,.F.);
#913=CARTESIAN_POINT('',(22.1361,0.,101.6));
#914=DIRECTION('',(0.,0.,1.));
#915=DIRECTION('',(1.,0.,0.));
#916=AXIS2_PLACEMENT_3D('',#913,#914,#915);
#917=CIRCLE('',#916,4.49580000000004);
#918=EDGE_CURVE('E385',#878,#910,#917,.T.);
#919=ORIENTED_EDGE('',*,*,#918,.F.);
#920=ORIENTED_EDGE('',*,*,#879,.T.);
#921=EDGE_LOOP('',(#904,#912,#919,#920));
#922=FACE_BOUND('',#921,.T.);
#923=ADVANCED_FACE('F622',(#922),#895,.T.);
#924=CARTESIAN_POINT('',(19.1389,-7.2136,101.6));
#925=DIRECTION('',(1.,0.,0.));
#926=DIRECTION('',(0.,0.,-1.));
#927=AXIS2_PLACEMENT_3D('',#924,#925,#926);
#928=PLANE('',#927);
#929=DIRECTION('',(0.,-1.,0.));
#930=VECTOR('',#929,1.);
#931=CARTESIAN_POINT('',(19.1389,-7.2136,0.));
#932=LINE('',#931,#930);
#933=CARTESIAN_POINT('',(19.1389,-7.2136,0.));
#934=VERTEX_POINT('',#933);
#935=EDGE_CURVE('E448',#902,#934,#932,.T.);
#936=ORIENTED_EDGE('',*,*,#935,.T.);
#937=DIRECTION('',(0.,0.,-1.));
#938=VECTOR('',#937,1.);
#939=CARTESIAN_POINT('',(19.1389,-7.2136,101.6));
#940=LINE('',#939,#938);
#941=CARTESIAN_POINT('',(19.1389,-7.2136,101.6));
#942=VERTEX_POINT('',#941);
#943=EDGE_CURVE('E463',#942,#934,#940,.T.);
#944=ORIENTED_EDGE('',*,*,#943,.F.);
#945=DIRECTION('',(0.,-1.,0.));
#946=VECTOR('',#945,1.);
#947=CARTESIAN_POINT('',(19.1389,-7.2136,101.6));
#948=LINE('',#947,#946);
#949=EDGE_CURVE('E387',#910,#942,#948,.T.);
#950=ORIENTED_EDGE('',*,*,#949,.F.);
#951=ORIENTED_EDGE('',*,*,#911,.T.);
#952=EDGE_LOOP('',(#936,#944,#950,#951));
#953=FACE_BOUND('',#952,.T.);
#954=ADVANCED_FACE('F618',(#953),#928,.F.);
#955=CARTESIAN_POINT('',(-19.1389,-7.2136,101.6));
#956=DIRECTION('',(0.,-1.,0.));
#957=DIRECTION('',(0.,0.,-1.));
#958=AXIS2_PLACEMENT_3D('',#955,#956,#957);
#959=PLANE('',#958);
#960=DIRECTION('',(0.,0.,1.));
#961=VECTOR('',#960,1.);
#962=CARTESIAN_POINT('',(7.14374999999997,-7.2136,152.4));
#963=LINE('',#962,#961);
#964=CARTESIAN_POINT('',(7.14375,-7.2136,73.81875));
#965=VERTEX_POINT('',#964);
#966=CARTESIAN_POINT('',(7.14375,-7.2136,88.10625));
#967=VERTEX_POINT('',#966);
#968=EDGE_CURVE('E305',#965,#967,#963,.T.);
#969=ORIENTED_EDGE('',*,*,#968,.T.);
#970=CARTESIAN_POINT('',(0.,-7.2136,88.10625));
#971=DIRECTION('',(0.,-1.,0.));
#972=DIRECTION('',(0.,0.,-1.));
#973=AXIS2_PLACEMENT_3D('',#970,#971,#972);
#974=CIRCLE('',#973,7.14375);
#975=CARTESIAN_POINT('',(-7.14375,-7.2136,88.10625));
#976=VERTEX_POINT('',#975);
#977=EDGE_CURVE('E309',#967,#976,#974,.T.);
#978=ORIENTED_EDGE('',*,*,#977,.T.);
#979=DIRECTION('',(0.,0.,-1.));
#980=VECTOR('',#979,1.);
#981=CARTESIAN_POINT('',(-7.14375,-7.2136,152.4));
#982=LINE('',#981,#980);
#983=CARTESIAN_POINT('',(-7.14375,-7.2136,73.81875));
#984=VERTEX_POINT('',#983);
#985=EDGE_CURVE('E286',#976,#984,#982,.T.);
#986=ORIENTED_EDGE('',*,*,#985,.T.);
#987=CARTESIAN_POINT('',(0.,-7.2136,73.81875));
#988=DIRECTION('',(0.,-1.,0.));
#989=DIRECTION('',(0.,0.,-1.));
#990=AXIS2_PLACEMENT_3D('',#987,#988,#989);
#991=CIRCLE('',#990,7.14375);
#992=EDGE_CURVE('E55',#984,#965,#991,.T.);
#993=ORIENTED_EDGE('',*,*,#992,.T.);
#994=EDGE_LOOP('',(#969,#978,#986,#993));
#995=FACE_BOUND('',#994,.T.);
#996=DIRECTION('',(0.,0.,1.));
#997=VECTOR('',#996,1.);
#998=CARTESIAN_POINT('',(7.14374999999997,-7.2136,101.6));
#999=LINE('',#998,#997);
#1000=CARTESIAN_POINT('',(7.14375,-7.2136,23.01875));
#1001=VERTEX_POINT('',#1000);
#1002=CARTESIAN_POINT('',(7.14375,-7.2136,37.30625));
#1003=VERTEX_POINT('',#1002);
#1004=EDGE_CURVE('E40',#1001,#1003,#999,.T.);
#1005=ORIENTED_EDGE('',*,*,#1004,.T.);
#1006=CARTESIAN_POINT('',(0.,-7.2136,37.30625));
#1007=DIRECTION('',(0.,-1.,0.));
#1008=DIRECTION('',(0.,0.,-1.));
#1009=AXIS2_PLACEMENT_3D('',#1006,#1007,#1008);
#1010=CIRCLE('',#1009,7.14375);
#1011=CARTESIAN_POINT('',(-7.14375,-7.2136,37.30625));
#1012=VERTEX_POINT('',#1011);
#1013=EDGE_CURVE('E11',#1003,#1012,#1010,.T.);
#1014=ORIENTED_EDGE('',*,*,#1013,.T.);
#1015=DIRECTION('',(0.,0.,-1.));
#1016=VECTOR('',#1015,1.);
#1017=CARTESIAN_POINT('',(-7.14375,-7.2136,101.6));
#1018=LINE('',#1017,#1016);
#1019=CARTESIAN_POINT('',(-7.14375,-7.2136,23.01875));
#1020=VERTEX_POINT('',#1019);
#1021=EDGE_CURVE('E544',#1012,#1020,#1018,.T.);
#1022=ORIENTED_EDGE('',*,*,#1021,.T.);
#1023=CARTESIAN_POINT('',(0.,-7.2136,23.01875));
#1024=DIRECTION('',(0.,-1.,0.));
#1025=DIRECTION('',(0.,0.,-1.));
#1026=AXIS2_PLACEMENT_3D('',#1023,#1024,#1025);
#1027=CIRCLE('',#1026,7.14375);
#1028=EDGE_CURVE('E547',#1020,#1001,#1027,.T.);
#1029=ORIENTED_EDGE('',*,*,#1028,.T.);
#1030=EDGE_LOOP('',(#1005,#1014,#1022,#1029));
#1031=FACE_BOUND('',#1030,.T.);
#1032=DIRECTION('',(-1.,0.,0.));
#1033=VECTOR('',#1032,1.);
#1034=CARTESIAN_POINT('',(-19.1389,-7.2136,0.));
#1035=LINE('',#1034,#1033);
#1036=CARTESIAN_POINT('',(-19.1389,-7.2136,0.));
#1037=VERTEX_POINT('',#1036);
#1038=EDGE_CURVE('E450',#934,#1037,#1035,.T.);
#1039=ORIENTED_EDGE('',*,*,#1038,.T.);
#1040=DIRECTION('',(0.,0.,-1.));
#1041=VECTOR('',#1040,1.);
#1042=CARTESIAN_POINT('',(-19.1389,-7.2136,101.6));
#1043=LINE('',#1042,#1041);
#1044=CARTESIAN_POINT('',(-19.1389,-7.2136,101.6));
#1045=VERTEX_POINT('',#1044);
#1046=EDGE_CURVE('E460',#1045,#1037,#1043,.T.);
#1047=ORIENTED_EDGE('',*,*,#1046,.F.);
#1048=DIRECTION('',(-1.,0.,0.));
#1049=VECTOR('',#1048,1.);
#1050=CARTESIAN_POINT('',(-19.1389,-7.2136,101.6));
#1051=LINE('',#1050,#1049);
#1052=EDGE_CURVE('E389',#942,#1045,#1051,.T.);
#1053=ORIENTED_EDGE('',*,*,#1052,.F.);
#1054=ORIENTED_EDGE('',*,*,#943,.T.);
#1055=EDGE_LOOP('',(#1039,#1047,#1053,#1054));
#1056=FACE_BOUND('',#1055,.T.);
#1057=ADVANCED_FACE('F551',(#995,#1031,#1056),#959,.F.);
#1058=CARTESIAN_POINT('',(-19.1389,-3.35097147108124,101.6));
#1059=DIRECTION('',(-1.,0.,0.));
#1060=DIRECTION('',(0.,0.,1.));
#1061=AXIS2_PLACEMENT_3D('',#1058,#1059,#1060);
#1062=PLANE('',#1061);
#1063=DIRECTION('',(0.,1.,0.));
#1064=VECTOR('',#1063,1.);
#1065=CARTESIAN_POINT('',(-19.1389,-3.35097147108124,0.));
#1066=LINE('',#1065,#1064);
#1067=CARTESIAN_POINT('',(-19.1389,-3.35097147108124,0.));
#1068=VERTEX_POINT('',#1067);
#1069=EDGE_CURVE('E452',#1037,#1068,#1066,.T.);
#1070=ORIENTED_EDGE('',*,*,#1069,.T.);
#1071=DIRECTION('',(0.,0.,-1.));
#1072=VECTOR('',#1071,1.);
#1073=CARTESIAN_POINT('',(-19.1389,-3.35097147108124,101.6));
#1074=LINE('',#1073,#1072);
#1075=CARTESIAN_POINT('',(-19.1389,-3.35097147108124,101.6));
#1076=VERTEX_POINT('',#1075);
#1077=EDGE_CURVE('E457',#1076,#1068,#1074,.T.);
#1078=ORIENTED_EDGE('',*,*,#1077,.F.);
#1079=DIRECTION('',(0.,1.,0.));
#1080=VECTOR('',#1079,1.);
#1081=CARTESIAN_POINT('',(-19.1389,-3.35097147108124,101.6));
#1082=LINE('',#1081,#1080);
#1083=EDGE_CURVE('E391',#1045,#1076,#1082,.T.);
#1084=ORIENTED_EDGE('',*,*,#1083,.F.);
#1085=ORIENTED_EDGE('',*,*,#1046,.T.);
#1086=EDGE_LOOP('',(#1070,#1078,#1084,#1085));
#1087=FACE_BOUND('',#1086,.T.);
#1088=ADVANCED_FACE('F609',(#1087),#1062,.F.);
#1089=CARTESIAN_POINT('',(-22.1361,0.,101.6));
#1090=DIRECTION('',(0.,0.,-1.));
#1091=DIRECTION('',(-1.,0.,0.));
#1092=AXIS2_PLACEMENT_3D('',#1089,#1090,#1091);
#1093=CYLINDRICAL_SURFACE('',#1092,4.49580000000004);
#1094=CARTESIAN_POINT('',(-22.1361,0.,0.));
#1095=DIRECTION('',(0.,0.,1.));
#1096=DIRECTION('',(1.,0.,0.));
#1097=AXIS2_PLACEMENT_3D('',#1094,#1095,#1096);
#1098=CIRCLE('',#1097,4.49580000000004);
#1099=EDGE_CURVE('E337',#1068,#29,#1098,.T.);
#1100=ORIENTED_EDGE('',*,*,#1099,.T.);
#1101=ORIENTED_EDGE('',*,*,#54,.F.);
#1102=CARTESIAN_POINT('',(-22.1361,0.,101.6));
#1103=DIRECTION('',(0.,0.,1.));
#1104=DIRECTION('',(1.,0.,0.));
#1105=AXIS2_PLACEMENT_3D('',#1102,#1103,#1104);
#1106=CIRCLE('',#1105,4.49580000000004);
#1107=EDGE_CURVE('E393',#1076,#47,#1106,.T.);
#1108=ORIENTED_EDGE('',*,*,#1107,.F.);
#1109=ORIENTED_EDGE('',*,*,#1077,.T.);
#1110=EDGE_LOOP('',(#1100,#1101,#1108,#1109));
#1111=FACE_BOUND('',#1110,.T.);
#1112=ADVANCED_FACE('F607',(#1111),#1093,.T.);
#1113=CARTESIAN_POINT('',(-22.1361,0.,101.6));
#1114=DIRECTION('',(0.,0.,1.));
#1115=DIRECTION('',(1.,0.,0.));
#1116=AXIS2_PLACEMENT_3D('',#1113,#1114,#1115);
#1117=PLANE('',#1116);
#1118=ORIENTED_EDGE('',*,*,#48,.T.);
#1119=ORIENTED_EDGE('',*,*,#84,.T.);
#1120=ORIENTED_EDGE('',*,*,#115,.T.);
#1121=ORIENTED_EDGE('',*,*,#146,.T.);
#1122=ORIENTED_EDGE('',*,*,#177,.T.);
#1123=ORIENTED_EDGE('',*,*,#210,.T.);
#1124=ORIENTED_EDGE('',*,*,#241,.T.);
#1125=ORIENTED_EDGE('',*,*,#274,.T.);
#1126=ORIENTED_EDGE('',*,*,#305,.T.);
#1127=ORIENTED_EDGE('',*,*,#338,.T.);
#1128=ORIENTED_EDGE('',*,*,#369,.T.);
#1129=ORIENTED_EDGE('',*,*,#402,.T.);
#1130=ORIENTED_EDGE('',*,*,#505,.T.);
#1131=ORIENTED_EDGE('',*,*,#538,.T.);
#1132=ORIENTED_EDGE('',*,*,#569,.T.);
#1133=ORIENTED_EDGE('',*,*,#602,.T.);
#1134=ORIENTED_EDGE('',*,*,#633,.T.);
#1135=ORIENTED_EDGE('',*,*,#666,.T.);
#1136=ORIENTED_EDGE('',*,*,#697,.T.);
#1137=ORIENTED_EDGE('',*,*,#730,.T.);
#1138=ORIENTED_EDGE('',*,*,#761,.T.);
#1139=ORIENTED_EDGE('',*,*,#792,.T.);
#1140=ORIENTED_EDGE('',*,*,#823,.T.);
#1141=ORIENTED_EDGE('',*,*,#854,.T.);
#1142=ORIENTED_EDGE('',*,*,#885,.T.);
#1143=ORIENTED_EDGE('',*,*,#918,.T.);
#1144=ORIENTED_EDGE('',*,*,#949,.T.);
#1145=ORIENTED_EDGE('',*,*,#1052,.T.);
#1146=ORIENTED_EDGE('',*,*,#1083,.T.);
#1147=ORIENTED_EDGE('',*,*,#1107,.T.);
#1148=EDGE_LOOP('',(#1118,#1119,#1120,#1121,#1122,#1123,#1124,#1125,#1126,#1127,#1128,#1129,
#1130,#1131,#1132,#1133,#1134,#1135,#1136,#1137,#1138,#1139,#1140,#1141,#1142,#1143,#1144,#1145,
#1146,#1147));
#1149=FACE_BOUND('',#1148,.T.);
#1150=ADVANCED_FACE('F602',(#1149),#1117,.T.);
#1151=CARTESIAN_POINT('',(-22.1361,0.,0.));
#1152=DIRECTION('',(0.,0.,1.));
#1153=DIRECTION('',(1.,0.,0.));
#1154=AXIS2_PLACEMENT_3D('',#1151,#1152,#1153);
#1155=PLANE('',#1154);
#1156=ORIENTED_EDGE('',*,*,#32,.F.);
#1157=ORIENTED_EDGE('',*,*,#1099,.F.);
#1158=ORIENTED_EDGE('',*,*,#1069,.F.);
#1159=ORIENTED_EDGE('',*,*,#1038,.F.);
#1160=ORIENTED_EDGE('',*,*,#935,.F.);
#1161=ORIENTED_EDGE('',*,*,#903,.F.);
#1162=ORIENTED_EDGE('',*,*,#871,.F.);
#1163=ORIENTED_EDGE('',*,*,#840,.F.);
#1164=ORIENTED_EDGE('',*,*,#809,.F.);
#1165=ORIENTED_EDGE('',*,*,#778,.F.);
#1166=ORIENTED_EDGE('',*,*,#747,.F.);
#1167=ORIENTED_EDGE('',*,*,#715,.F.);
#1168=ORIENTED_EDGE('',*,*,#683,.F.);
#1169=ORIENTED_EDGE('',*,*,#651,.F.);
#1170=ORIENTED_EDGE('',*,*,#619,.F.);
#1171=ORIENTED_EDGE('',*,*,#587,.F.);
#1172=ORIENTED_EDGE('',*,*,#555,.F.);
#1173=ORIENTED_EDGE('',*,*,#523,.F.);
#1174=ORIENTED_EDGE('',*,*,#491,.F.);
#1175=ORIENTED_EDGE('',*,*,#387,.F.);
#1176=ORIENTED_EDGE('',*,*,#355,.F.);
#1177=ORIENTED_EDGE('',*,*,#323,.F.);
#1178=ORIENTED_EDGE('',*,*,#291,.F.);
#1179=ORIENTED_EDGE('',*,*,#259,.F.);
#1180=ORIENTED_EDGE('',*,*,#227,.F.);
#1181=ORIENTED_EDGE('',*,*,#195,.F.);
#1182=ORIENTED_EDGE('',*,*,#163,.F.);
#1183=ORIENTED_EDGE('',*,*,#132,.F.);
#1184=ORIENTED_EDGE('',*,*,#101,.F.);
#1185=ORIENTED_EDGE('',*,*,#70,.F.);
#1186=EDGE_LOOP('',(#1156,#1157,#1158,#1159,#1160,#1161,#1162,#1163,#1164,#1165,#1166,#1167,
#1168,#1169,#1170,#1171,#1172,#1173,#1174,#1175,#1176,#1177,#1178,#1179,#1180,#1181,#1182,#1183,
#1184,#1185));
#1187=FACE_BOUND('',#1186,.T.);
#1188=ADVANCED_FACE('F595',(#1187),#1155,.F.);
#1189=CARTESIAN_POINT('',(0.,11.938,37.30625));
#1190=DIRECTION('',(0.,-1.,0.));
#1191=DIRECTION('',(0.,0.,-1.));
#1192=AXIS2_PLACEMENT_3D('',#1189,#1190,#1191);
#1193=CYLINDRICAL_SURFACE('',#1192,7.14375);
#1194=DIRECTION('',(0.,-1.,0.));
#1195=VECTOR('',#1194,1.);
#1196=CARTESIAN_POINT('',(7.14375,11.938,37.30625));
#1197=LINE('',#1196,#1195);
#1198=EDGE_CURVE('E324',#1003,#465,#1197,.T.);
#1199=ORIENTED_EDGE('',*,*,#1198,.T.);
#1200=ORIENTED_EDGE('',*,*,#466,.T.);
#1201=DIRECTION('',(0.,-1.,0.));
#1202=VECTOR('',#1201,1.);
#1203=CARTESIAN_POINT('',(-7.14375,11.938,37.30625));
#1204=LINE('',#1203,#1202);
#1205=EDGE_CURVE('E323',#1012,#454,#1204,.T.);
#1206=ORIENTED_EDGE('',*,*,#1205,.F.);
#1207=ORIENTED_EDGE('',*,*,#1013,.F.);
#1208=EDGE_LOOP('',(#1199,#1200,#1206,#1207));
#1209=FACE_BOUND('',#1208,.T.);
#1210=ADVANCED_FACE('F567',(#1209),#1193,.F.);
#1211=CARTESIAN_POINT('',(7.14375,11.938,37.30625));
#1212=DIRECTION('',(1.,0.,0.));
#1213=DIRECTION('',(0.,0.,-1.));
#1214=AXIS2_PLACEMENT_3D('',#1211,#1212,#1213);
#1215=PLANE('',#1214);
#1216=DIRECTION('',(0.,-1.,0.));
#1217=VECTOR('',#1216,1.);
#1218=CARTESIAN_POINT('',(7.14375,11.938,23.01875));
#1219=LINE('',#1218,#1217);
#1220=EDGE_CURVE('E327',#1001,#473,#1219,.T.);
#1221=ORIENTED_EDGE('',*,*,#1220,.T.);
#1222=ORIENTED_EDGE('',*,*,#474,.T.);
#1223=ORIENTED_EDGE('',*,*,#1198,.F.);
#1224=ORIENTED_EDGE('',*,*,#1004,.F.);
#1225=EDGE_LOOP('',(#1221,#1222,#1223,#1224));
#1226=FACE_BOUND('',#1225,.T.);
#1227=ADVANCED_FACE('F557',(#1226),#1215,.F.);
#1228=CARTESIAN_POINT('',(0.,11.938,23.01875));
#1229=DIRECTION('',(0.,-1.,0.));
#1230=DIRECTION('',(0.,0.,-1.));
#1231=AXIS2_PLACEMENT_3D('',#1228,#1229,#1230);
#1232=CYLINDRICAL_SURFACE('',#1231,7.14375);
#1233=DIRECTION('',(0.,-1.,0.));
#1234=VECTOR('',#1233,1.);
#1235=CARTESIAN_POINT('',(-7.14375,11.938,23.01875));
#1236=LINE('',#1235,#1234);
#1237=EDGE_CURVE('E329',#1020,#456,#1236,.T.);
#1238=ORIENTED_EDGE('',*,*,#1237,.T.);
#1239=ORIENTED_EDGE('',*,*,#481,.T.);
#1240=ORIENTED_EDGE('',*,*,#1220,.F.);
#1241=ORIENTED_EDGE('',*,*,#1028,.F.);
#1242=EDGE_LOOP('',(#1238,#1239,#1240,#1241));
#1243=FACE_BOUND('',#1242,.T.);
#1244=ADVANCED_FACE('F559',(#1243),#1232,.F.);
#1245=CARTESIAN_POINT('',(-7.14375,11.938,23.01875));
#1246=DIRECTION('',(-1.,0.,0.));
#1247=DIRECTION('',(0.,0.,1.));
#1248=AXIS2_PLACEMENT_3D('',#1245,#1246,#1247);
#1249=PLANE('',#1248);
#1250=ORIENTED_EDGE('',*,*,#1205,.T.);
#1251=ORIENTED_EDGE('',*,*,#457,.T.);
#1252=ORIENTED_EDGE('',*,*,#1237,.F.);
#1253=ORIENTED_EDGE('',*,*,#1021,.F.);
#1254=EDGE_LOOP('',(#1250,#1251,#1252,#1253));
#1255=FACE_BOUND('',#1254,.T.);
#1256=ADVANCED_FACE('F569',(#1255),#1249,.F.);
#1257=CARTESIAN_POINT('',(0.,11.938,88.10625));
#1258=DIRECTION('',(0.,-1.,0.));
#1259=DIRECTION('',(0.,0.,-1.));
#1260=AXIS2_PLACEMENT_3D('',#1257,#1258,#1259);
#1261=CYLINDRICAL_SURFACE('',#1260,7.14375);
#1262=DIRECTION('',(0.,-1.,0.));
#1263=VECTOR('',#1262,1.);
#1264=CARTESIAN_POINT('',(7.14375,11.938,88.10625));
#1265=LINE('',#1264,#1263);
#1266=EDGE_CURVE('E303',#967,#429,#1265,.T.);
#1267=ORIENTED_EDGE('',*,*,#1266,.T.);
#1268=ORIENTED_EDGE('',*,*,#430,.T.);
#1269=DIRECTION('',(0.,-1.,0.));
#1270=VECTOR('',#1269,1.);
#1271=CARTESIAN_POINT('',(-7.14375,11.938,88.10625));
#1272=LINE('',#1271,#1270);
#1273=EDGE_CURVE('E283',#976,#418,#1272,.T.);
#1274=ORIENTED_EDGE('',*,*,#1273,.F.);
#1275=ORIENTED_EDGE('',*,*,#977,.F.);
#1276=EDGE_LOOP('',(#1267,#1268,#1274,#1275));
#1277=FACE_BOUND('',#1276,.T.);
#1278=ADVANCED_FACE('F571',(#1277),#1261,.F.);
#1279=CARTESIAN_POINT('',(7.14375,11.938,88.10625));
#1280=DIRECTION('',(1.,0.,0.));
#1281=DIRECTION('',(0.,0.,-1.));
#1282=AXIS2_PLACEMENT_3D('',#1279,#1280,#1281);
#1283=PLANE('',#1282);
#1284=DIRECTION('',(0.,-1.,0.));
#1285=VECTOR('',#1284,1.);
#1286=CARTESIAN_POINT('',(7.14375,11.938,73.81875));
#1287=LINE('',#1286,#1285);
#1288=EDGE_CURVE('E296',#965,#437,#1287,.T.);
#1289=ORIENTED_EDGE('',*,*,#1288,.T.);
#1290=ORIENTED_EDGE('',*,*,#438,.T.);
#1291=ORIENTED_EDGE('',*,*,#1266,.F.);
#1292=ORIENTED_EDGE('',*,*,#968,.F.);
#1293=EDGE_LOOP('',(#1289,#1290,#1291,#1292));
#1294=FACE_BOUND('',#1293,.T.);
#1295=ADVANCED_FACE('F577',(#1294),#1283,.F.);
#1296=CARTESIAN_POINT('',(0.,11.938,73.81875));
#1297=DIRECTION('',(0.,-1.,0.));
#1298=DIRECTION('',(0.,0.,-1.));
#1299=AXIS2_PLACEMENT_3D('',#1296,#1297,#1298);
#1300=CYLINDRICAL_SURFACE('',#1299,7.14375);
#1301=DIRECTION('',(0.,-1.,0.));
#1302=VECTOR('',#1301,1.);
#1303=CARTESIAN_POINT('',(-7.14375,11.938,73.81875));
#1304=LINE('',#1303,#1302);
#1305=EDGE_CURVE('E281',#984,#420,#1304,.T.);
#1306=ORIENTED_EDGE('',*,*,#1305,.T.);
#1307=ORIENTED_EDGE('',*,*,#445,.T.);
#1308=ORIENTED_EDGE('',*,*,#1288,.F.);
#1309=ORIENTED_EDGE('',*,*,#992,.F.);
#1310=EDGE_LOOP('',(#1306,#1307,#1308,#1309));
#1311=FACE_BOUND('',#1310,.T.);
#1312=ADVANCED_FACE('F288',(#1311),#1300,.F.);
#1313=CARTESIAN_POINT('',(-7.14375,11.938,73.81875));
#1314=DIRECTION('',(-1.,0.,0.));
#1315=DIRECTION('',(0.,0.,1.));
#1316=AXIS2_PLACEMENT_3D('',#1313,#1314,#1315);
#1317=PLANE('',#1316);
#1318=ORIENTED_EDGE('',*,*,#1273,.T.);
#1319=ORIENTED_EDGE('',*,*,#421,.T.);
#1320=ORIENTED_EDGE('',*,*,#1305,.F.);
#1321=ORIENTED_EDGE('',*,*,#985,.F.);
#1322=EDGE_LOOP('',(#1318,#1319,#1320,#1321));
#1323=FACE_BOUND('',#1322,.T.);
#1324=ADVANCED_FACE('F280',(#1323),#1317,.F.);
#1325=CLOSED_SHELL('',(#58,#89,#120,#151,#182,#215,#246,#279,#310,#343,#374,#407,#510,#543,#574,
#607,#638,#671,#702,#735,#766,#797,#828,#859,#890,#923,#954,#1057,#1088,#1112,#1150,#1188,#1210,
#1227,#1244,#1256,#1278,#1295,#1312,#1324));
#1326=MANIFOLD_SOLID_BREP('B2',#1325);
#1327=ADVANCED_BREP_SHAPE_REPRESENTATION('',(#18,#1326),#14);
#1328=SHAPE_DEFINITION_REPRESENTATION(#9,#1327);
ENDSEC;
END-ISO-10303-21;
